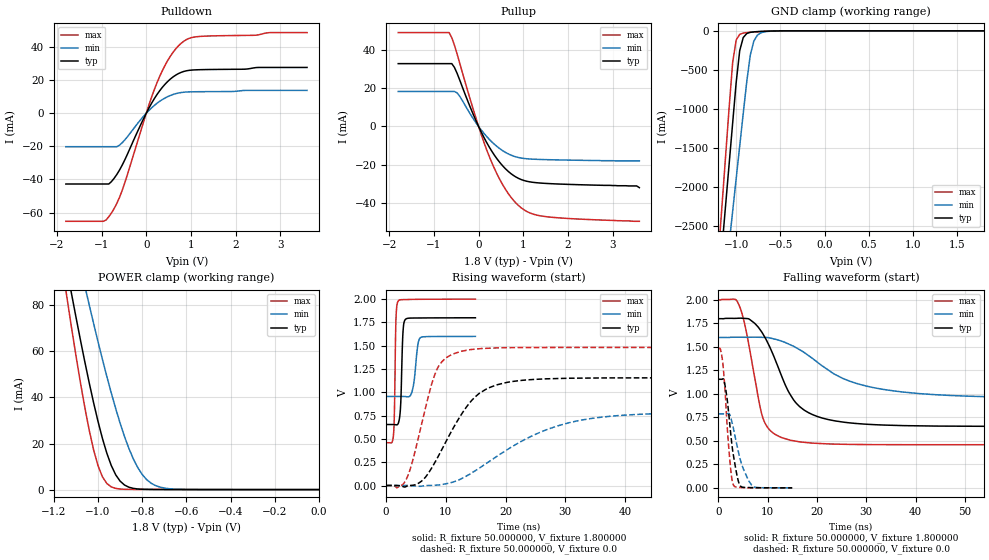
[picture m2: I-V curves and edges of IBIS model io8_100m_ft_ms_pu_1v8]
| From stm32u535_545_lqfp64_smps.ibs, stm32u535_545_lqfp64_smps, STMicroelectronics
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|   Model io8_100m_ft_ms_pu_1v8
[Model]  io8_100m_ft_ms_pu_1v8
Model_type I/O
Polarity   Non-Inverting
Enable   Active-Low
Vinl =   0.540000V
Vinh =   1.260000V
Vmeas =  0.900000V
Cref =   50.000000pF
Rref =   100.000000M
Vref =   0.0V
C_comp   3.148300pF   3.147400pF   3.196500pF
[Temperature Range]   25.000000   0.140000k   -40.000000
[Pullup Reference]   1.800000V   1.600000V   2.000000V
[Pulldown Reference]   0.0V   0.0V   0.0V
[POWER Clamp Reference]   1.800000V   1.600000V   2.000000V
[GND Clamp Reference]   0.0V   0.0V   0.0V
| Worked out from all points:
|   slope of the pulldown table from 0 to 0.27 V, typ, clamps not added: 21.7 ohm
|   slope of the pullup table from 0 to 0.27 V, typ, clamps not added: 22.6 ohm
|   GND clamp passes 1 mA (typ) near -0.51 V on its own axis
|   POWER clamp passes 1 mA (typ) near -0.86 V on its own axis
|   rising waveform, R_fixture 50.000000, V_fixture 1.800000: 20-80 % time 318ps typ, 631ps min, 230ps max; typ from 0.655 V to 1.8 V
|   rising waveform, R_fixture 50.000000, V_fixture 0.0: 20-80 % time 6.48ns typ, 13.4ns min, 3.57ns max; typ from 0.001 V to 1.16 V
|   falling waveform, R_fixture 50.000000, V_fixture 1.800000: 20-80 % time 6.36ns typ, 13.5ns min, 3.36ns max; typ from 1.8 V to 0.655 V
|   falling waveform, R_fixture 50.000000, V_fixture 0.0: 20-80 % time 1.6ns typ, 2.38ns min, 1.18ns max; typ from 1.16 V to 0.001 V
[Pulldown]
|Voltage   I(typ)   I(min)   I(max)
-1.8V     -42.74mA   -20.21mA   -65.25mA
-960mV    -42.74mA   -20.21mA   -65.25mA
-780mV    -41.3mA    -20.21mA   -60.25mA
-660mV    -37mA      -20.2mA    -54.5mA
-540mV    -31.39mA   -17.82mA   -46.65mA
0V        0A         0A         0A
240mV     11.28mA    6.002mA    18.38mA
480mV     19.17mA    10.02mA    31.83mA
780mV     24.67mA    12.5mA     42.21mA
960mV     25.9mA     12.9mA     45.21mA
1.2V      26.29mA    13.01mA    46.37mA
3.6V      27.65mA    13.81mA    48.71mA
[Pullup]
|Voltage   I(typ)   I(min)   I(max)
-1.8V     32.87mA    18.3mA     49.12mA
-660mV    32.87mA    18.3mA     49.12mA
-600mV    32.87mA    18.3mA     46.4mA
-480mV    27.73mA    17.56mA    37.8mA
-60mV     3.108mA    1.975mA    4.436mA
240mV     -10.82mA   -6.752mA   -15.73mA
420mV     -17.18mA   -10.64mA   -25.23mA
600mV     -22.1mA    -13.54mA   -32.82mA
960mV     -27.82mA   -16.55mA   -42.66mA
1.2V      -29.16mA   -17.09mA   -45.68mA
1.56V     -29.85mA   -17.37mA   -47.3mA
3.6V      -32mA      -18mA      -49.6mA
[GND_clamp]
|Voltage   I(typ)   I(min)   I(max)
-1.8V     -9.707A    -9.942A    -9.774A
-1.2V     -3.309A    -4.006A    -2.864A
-1.16V    -2.777A    -3.584A    -2.239A
-1.12V    -2.246A    -3.162A    -1.614A
-1.04V    -1.186A    -2.319A    -408.6mA
-1V       -663.9mA   -1.898A    -117.8mA
-960mV    -254mA     -1.478A    -45.14mA
-920mV    -86.03mA   -1.06A     -28.58mA
-840mV    -19.12mA   -308.9mA   -18.74mA
-800mV    -13.39mA   -130.8mA   -15.31mA
-720mV    -7.948mA   -25.37mA   -9.381mA
1.8V      0A         14.97nA    0A
[POWER_clamp]
|Voltage   I(typ)   I(min)   I(max)
-1.8V     470.9mA    433.7mA    554.6mA
-1.14V    95.28mA    122.7mA    82.88mA
-1.12V    85mA       114mA      70.34mA
-1.06V    55.55mA    88.43mA    35.73mA
-1.04V    46.38mA    80.17mA    25.83mA
-1V       29.54mA    64.14mA    10.37mA
-940mV    10.43mA    41.88mA    1.177mA
-900mV    3.66mA     28.79mA    250.5uA
-840mV    527.2uA    13.26mA    95.74uA
-800mV    153.8uA    6.55mA     88.56uA
-740mV    60.02uA    1.742mA    70.74uA
0V        0A         18.15nA    0A
[Ramp]
| variable   typ   min   max
dV/dt_r  0.69293/6.46989n   0.47197/13.34513n   0.88855/3.56212n
dV/dt_f  0.68715/6.35794n   0.38626/13.46817n   0.92439/3.34580n
R_load = 50.000000
[Rising Waveform]
R_fixture= 50.000000
V_fixture= 1.800000
V_fixture_min= 1.600000
V_fixture_max= 2.000000
|time   V(typ)   V(min)   V(max)
0s        654.8mV    956mV      459.4mV
1.231ns   654.6mV    956mV      545mV
1.652ns   651.9mV    956mV      1.797V
2.012ns   664.8mV    956.1mV    1.98V
2.432ns   868mV      956.1mV    1.993V
2.853ns   1.677V     955.8mV    1.995V
3.213ns   1.782V     954.8mV    1.995V
4.414ns   1.797V     1.027V     1.997V
5.676ns   1.798V     1.583V     1.998V
14.95ns   1.8V       1.6V       2V
[Rising Waveform]
R_fixture= 50.000000
V_fixture= 0.0
V_fixture_min= 0.0
V_fixture_max= 0.0
|time   V(typ)   V(min)   V(max)
0s        614.9uV    691.2uV    580.3uV
3.203ns   -15.29mV   805.6uV    47.33mV
6.006ns   51.57mV    -6.151mV   676.5mV
8.408ns   275.5mV    4.433mV    1.233V
12.61ns   763.6mV    73.78mV    1.441V
15.62ns   989.8mV    187.2mV    1.468V
18.42ns   1.078V     307.6mV    1.476V
26.83ns   1.145V     598mV      1.481V
35.44ns   1.154V     728.7mV    1.481V
99.7ns    1.155V     787.4mV    1.481V
[Falling Waveform]
R_fixture= 50.000000
V_fixture= 1.800000
V_fixture_min= 1.600000
V_fixture_max= 2.000000
|time   V(typ)   V(min)   V(max)
0s        1.8V       1.6V       2V
3.804ns   1.804V     1.603V     1.984V
5.405ns   1.802V     1.602V     1.721V
9.209ns   1.62V      1.601V     715.5mV
14.41ns   1.005V     1.526V     509.6mV
17.22ns   833.9mV    1.447V     485.7mV
21.02ns   743.6mV    1.299V     471.3mV
27.63ns   686.7mV    1.118V     462.3mV
37.04ns   663.3mV    1.022V     459.8mV
99.7ns    654.8mV    956mV      459.4mV
[Falling Waveform]
R_fixture= 50.000000
V_fixture= 0.0
V_fixture_min= 0.0
V_fixture_max= 0.0
|time   V(typ)   V(min)   V(max)
0s        1.155V     787.4mV    1.481V
750.8ps   1.156V     787.4mV    1.378V
1.321ns   1.092V     787.4mV    1.045V
1.802ns   924.2mV    788.9mV    624.3mV
2.282ns   680mV      779.7mV    305.1mV
2.673ns   482.7mV    712.5mV    111.3mV
3.033ns   344.4mV    630.9mV    30.74mV
4.234ns   40.12mV    341.2mV    5.571mV
6.727ns   3.287mV    29.26mV    1.626mV
14.95ns   614.9uV    691.2uV    580.3uV
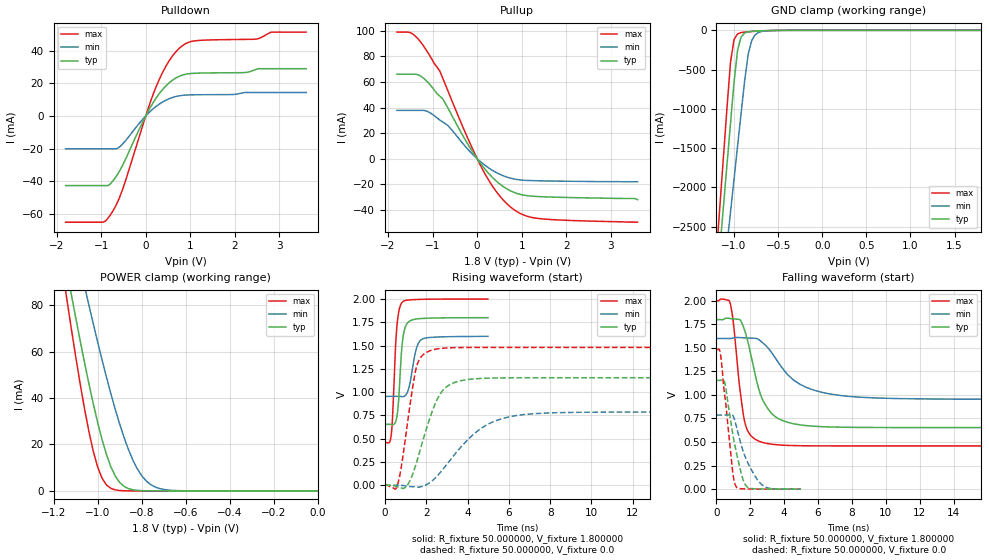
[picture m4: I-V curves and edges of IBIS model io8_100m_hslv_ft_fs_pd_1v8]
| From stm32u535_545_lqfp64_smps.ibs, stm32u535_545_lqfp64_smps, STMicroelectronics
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|   Model io8_100m_hslv_ft_fs_pd_1v8
[Model]  io8_100m_hslv_ft_fs_pd_1v8
Model_type I/O
Polarity   Non-Inverting
Enable   Active-Low
Vinl =   0.540000V
Vinh =   1.260000V
Vmeas =  0.900000V
Cref =   50.000000pF
Rref =   100.000000M
Vref =   0.0V
C_comp   3.235100pF   3.233200pF   3.282800pF
[Temperature Range]   25.000000   0.140000k   -40.000000
[Pullup Reference]   1.800000V   1.600000V   2.000000V
[Pulldown Reference]   0.0V   0.0V   0.0V
[POWER Clamp Reference]   1.800000V   1.600000V   2.000000V
[GND Clamp Reference]   0.0V   0.0V   0.0V
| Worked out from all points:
|   slope of the pulldown table from 0 to 0.27 V, typ, clamps not added: 21.7 ohm
|   slope of the pullup table from 0 to 0.27 V, typ, clamps not added: 22.6 ohm
|   GND clamp passes 1 mA (typ) near -0.51 V on its own axis
|   POWER clamp passes 1 mA (typ) near -0.86 V on its own axis
|   rising waveform, R_fixture 50.000000, V_fixture 1.800000: 20-80 % time 212ps typ, 327ps min, 198ps max; typ from 0.654 V to 1.8 V
|   rising waveform, R_fixture 50.000000, V_fixture 0.0: 20-80 % time 1.02ns typ, 2.03ns min, 582ps max; typ from 0 V to 1.15 V
|   falling waveform, R_fixture 50.000000, V_fixture 1.800000: 20-80 % time 1.09ns typ, 2.1ns min, 568ps max; typ from 1.8 V to 0.654 V
|   falling waveform, R_fixture 50.000000, V_fixture 0.0: 20-80 % time 708ps typ, 987ps min, 509ps max; typ from 1.15 V to 0 V
[Pulldown]
|Voltage   I(typ)   I(min)   I(max)
-1.8V     -42.74mA   -20.21mA   -65.25mA
-960mV    -42.74mA   -20.21mA   -65.25mA
-780mV    -41.3mA    -20.21mA   -60.25mA
-540mV    -31.39mA   -17.82mA   -46.65mA
0V        0A         -500fA     0A
240mV     11.28mA    6.002mA    18.38mA
480mV     19.17mA    10.02mA    31.83mA
780mV     24.67mA    12.5mA     42.21mA
1.14V     26.24mA    12.99mA    46.23mA
2.46V     28.42mA    14.39mA    47.14mA
2.82V     29mA       14.39mA    51.49mA
3.6V      29mA       14.39mA    51.49mA
[Pullup]
|Voltage   I(typ)   I(min)   I(max)
-1.8V     66.02mA    37.77mA    98.95mA
-1.44V    66.02mA    37.77mA    97.33mA
-1.14V    60.88mA    37.29mA    84.79mA
-840mV    48.93mA    30.23mA    68.56mA
-660mV    39.81mA    25.95mA    53.26mA
-300mV    16.72mA    11mA       23.08mA
120mV     -5.748mA   -3.603mA   -8.317mA
420mV     -17.18mA   -10.64mA   -25.23mA
780mV     -25.61mA   -15.48mA   -38.6mA
1.08V     -28.66mA   -16.9mA    -44.47mA
1.38V     -29.58mA   -17.26mA   -46.72mA
3.6V      -32mA      -18mA      -49.6mA
[GND_clamp]
|Voltage   I(typ)   I(min)   I(max)
-1.8V     -9.707A    -9.942A    -9.774A
-1.2V     -3.309A    -4.006A    -2.865A
-1.16V    -2.777A    -3.584A    -2.239A
-1.12V    -2.246A    -3.162A    -1.614A
-1.04V    -1.186A    -2.319A    -408.7mA
-1V       -663.9mA   -1.898A    -117.8mA
-960mV    -254mA     -1.478A    -45.15mA
-920mV    -86.04mA   -1.06A     -28.6mA
-840mV    -19.13mA   -308.9mA   -18.75mA
-800mV    -13.4mA    -130.8mA   -15.33mA
-720mV    -7.959mA   -25.38mA   -9.395mA
1.8V      45.71uA    33.33uA    56.11uA
[POWER_clamp]
|Voltage   I(typ)   I(min)   I(max)
-1.8V     470.8mA    433.7mA    554.6mA
-1.14V    95.25mA    122.7mA    82.82mA
-1.12V    84.97mA    114mA      70.27mA
-1.06V    55.51mA    88.42mA    35.67mA
-1.04V    46.34mA    80.15mA    25.76mA
-1V       29.51mA    64.13mA    10.3mA
-940mV    10.39mA    41.86mA    1.109mA
-900mV    3.624mA    28.77mA    182.8uA
-840mV    490.7uA    13.24mA    11.35uA
-800mV    116.8uA    6.532mA    1.77uA
-740mV    13.2uA     1.723mA    109.2nA
0V        0A         18.72nA    0A
[Ramp]
| variable   typ   min   max
dV/dt_r  0.69258/1.02276n   0.47168/2.03115n   0.88830/0.58108n
dV/dt_f  0.68752/1.08521n   0.38689/2.09532n   0.92452/0.56669n
R_load = 50.000000
[Rising Waveform]
R_fixture= 50.000000
V_fixture= 1.800000
V_fixture_min= 1.600000
V_fixture_max= 2.000000
|time   V(typ)   V(min)   V(max)
0s        653.7mV    954.5mV    458.6mV
310.3ps   652.7mV    954.7mV    549.8mV
370.4ps   650.7mV    954.8mV    746.8mV
550.6ps   707.2mV    955mV      1.628V
650.7ps   879mV      955mV      1.839V
810.8ps   1.456V     952.3mV    1.957V
1.061ns   1.733V     986.6mV    1.987V
1.512ns   1.785V     1.46V      1.994V
1.782ns   1.791V     1.566V     1.996V
4.985ns   1.799V     1.599V     1.999V
[Rising Waveform]
R_fixture= 50.000000
V_fixture= 0.0
V_fixture_min= 0.0
V_fixture_max= 0.0
|time   V(typ)   V(min)   V(max)
0s        -120.5uV   -24.73uV   -133uV
600.6ps   -17.03mV   -53.11uV   -896uV
1.041ns   -10.8mV    -9.086mV   586mV
1.522ns   239.4mV    -19.39mV   1.267V
2.242ns   764.7mV    40.38mV    1.449V
2.763ns   1.008V     159.9mV    1.47V
3.363ns   1.103V     327.7mV    1.478V
4.805ns   1.148V     631.7mV    1.48V
6.206ns   1.153V     742.7mV    1.48V
19.94ns   1.155V     786.3mV    1.48V
[Falling Waveform]
R_fixture= 50.000000
V_fixture= 1.800000
V_fixture_min= 1.600000
V_fixture_max= 2.000000
|time   V(typ)   V(min)   V(max)
0s        1.799V     1.599V     1.999V
800.8ps   1.811V     1.599V     1.983V
1.001ns   1.807V     1.606V     1.768V
1.361ns   1.8V       1.609V     1.103V
1.642ns   1.699V     1.606V     741.3mV
2.482ns   1.075V     1.589V     511.5mV
3.564ns   759.1mV    1.369V     471.5mV
4.525ns   695.2mV    1.162V     462.8mV
6.326ns   662.6mV    1.024V     459mV
19.94ns   653.7mV    954.5mV    458.6mV
[Falling Waveform]
R_fixture= 50.000000
V_fixture= 0.0
V_fixture_min= 0.0
V_fixture_max= 0.0
|time   V(typ)   V(min)   V(max)
0s        1.155V     786.3mV    1.48V
240.2ps   1.155V     786.3mV    1.433V
480.5ps   1.139V     786.4mV    1.011V
971ps     582.1mV    780.6mV    173.5mV
1.171ns   396.8mV    672.3mV    25.18mV
1.502ns   144.4mV    447.4mV    4.102mV
1.712ns   46.4mV     338.6mV    2.742mV
2.573ns   2.51mV     65.95mV    737.1uV
3.273ns   945uV      5.496mV    216.1uV
4.985ns   -120.5uV   -24.73uV   -133uV
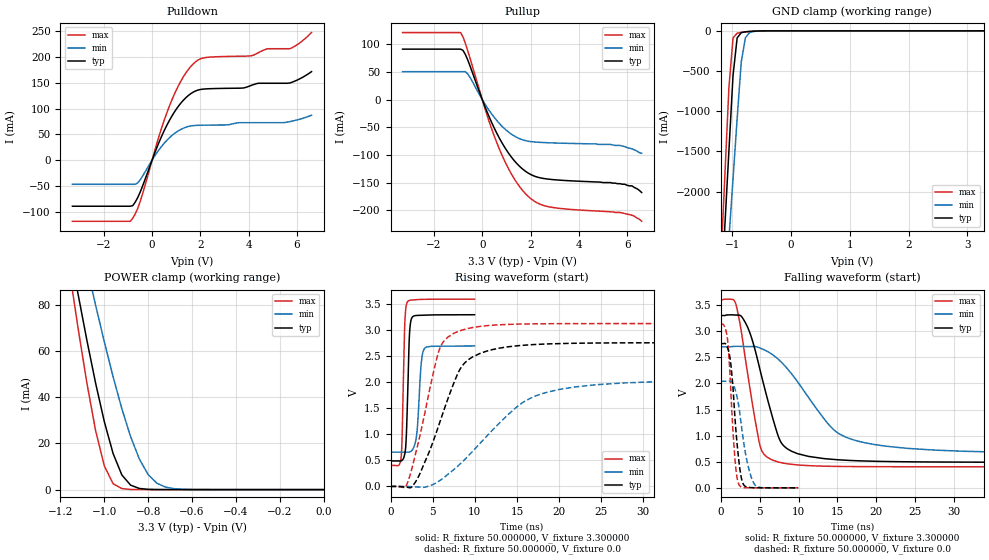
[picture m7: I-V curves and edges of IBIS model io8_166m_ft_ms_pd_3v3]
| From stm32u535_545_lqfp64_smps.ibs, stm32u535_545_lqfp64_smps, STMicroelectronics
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|   Model io8_166m_ft_ms_pd_3v3
[Model]  io8_166m_ft_ms_pd_3v3
Model_type I/O
Polarity   Non-Inverting
Enable   Active-Low
Vinl =   0.990000V
Vinh =   2.310000V
Vmeas =  1.650000V
Cref =   50.000000pF
Rref =   100.000000M
Vref =   0.0V
C_comp   3.517200pF   3.489400pF   3.557800pF
[Temperature Range]   25.000000   0.140000k   -40.000000
[Pullup Reference]   3.300000V   2.700000V   3.600000V
[Pulldown Reference]   0.0V   0.0V   0.0V
[POWER Clamp Reference]   3.300000V   2.700000V   3.600000V
[GND Clamp Reference]   0.0V   0.0V   0.0V
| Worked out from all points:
|   slope of the pulldown table from 0 to 0.495 V, typ, clamps not added: 8.73 ohm
|   slope of the pullup table from 0 to 0.495 V, typ, clamps not added: 9.64 ohm
|   GND clamp passes 1 mA (typ) near -0.50 V on its own axis
|   POWER clamp passes 1 mA (typ) near -0.85 V on its own axis
|   rising waveform, R_fixture 50.000000, V_fixture 3.300000: 20-80 % time 306ps typ, 454ps min, 272ps max; typ from 0.49 V to 3.3 V
|   rising waveform, R_fixture 50.000000, V_fixture 0.0: 20-80 % time 3.81ns typ, 7.8ns min, 2.6ns max; typ from 0 V to 2.76 V
|   falling waveform, R_fixture 50.000000, V_fixture 3.300000: 20-80 % time 3.02ns typ, 6.39ns min, 2.05ns max; typ from 3.3 V to 0.49 V
|   falling waveform, R_fixture 50.000000, V_fixture 0.0: 20-80 % time 900ps typ, 1.3ns min, 735ps max; typ from 2.76 V to 0 V
[Pulldown]
|Voltage   I(typ)   I(min)   I(max)
-3.3V     -89.72mA   -47.06mA   -119mA
-900mV    -89.72mA   -47.06mA   -119mA
-500mV    -62.92mA   -38.71mA   -81.44mA
300mV     36.2mA     21.01mA    48.7mA
800mV     84.07mA    46.96mA    114.9mA
1.3V      116.7mA    62.09mA    162.4mA
1.8V      134.4mA    67.39mA    191.2mA
2.3V      138.6mA    67.98mA    199.8mA
4.1V      145.1mA    72.79mA    202.7mA
4.8V      149.4mA    72.79mA    216.5mA
5.7V      149.8mA    74.8mA     216.5mA
6.6V      171.9mA    87.1mA     247.9mA
[Pullup]
|Voltage   I(typ)   I(min)   I(max)
-3.3V     91.09mA    50.39mA    121mA
-900mV    91.09mA    50.39mA    121mA
-800mV    88.97mA    50.39mA    113.5mA
-600mV    71.54mA    46.26mA    88.13mA
200mV     -22.26mA   -14.13mA   -28.39mA
700mV     -69mA      -42.82mA   -88.5mA
1.3V      -109.1mA   -65.19mA   -141.4mA
2V        -135.3mA   -75.91mA   -178.7mA
2.9V      -144.6mA   -78.33mA   -194.9mA
5.3V      -150mA     -81mA      -203mA
6.2V      -156mA     -89mA      -209mA
6.6V      -168mA     -97mA      -220mA
[GND_clamp]
|Voltage   I(typ)   I(min)   I(max)
-3.3V     -9.098A    -9.372A    -9.671A
-1.2V     -3.386A    -4.091A    -2.933A
-1.13V    -2.437A    -3.34A     -1.815A
-1.06V    -1.49A     -2.588A    -705.6mA
-990mV    -555.7mA   -1.839A    -89.05mA
-920mV    -88.14mA   -1.093A    -28.79mA
-850mV    -22.37mA   -387.4mA   -19.86mA
-780mV    -12.13mA   -88.01mA   -13.89mA
-710mV    -7.72mA    -22.53mA   -8.86mA
-640mV    -4.556mA   -7.872mA   -4.884mA
-360mV    -39.7uA    -179.9uA   -19.45uA
3.28V     83.52uA    56.87uA    102.4uA
[POWER_clamp]
|Voltage   I(typ)   I(min)   I(max)
-3.28V    1.355A     1.167A     1.664A
-1.16V    105.7mA    131.6mA    95.69mA
-1.12V    84.97mA    114mA      70.27mA
-1.08V    65.05mA    96.83mA    46.54mA
-1.04V    46.34mA    80.15mA    25.76mA
-1V       29.51mA    64.13mA    10.3mA
-960mV    15.69mA    48.99mA    2.571mA
-920mV    6.373mA    35.1mA     455.6uA
-840mV    490.7uA    13.24mA    11.36uA
-760mV    27.33uA    2.767mA    278.3nA
-640mV    347.6nA    134.1uA    16.77nA
0V        0A         19.95nA    0A
[Ramp]
| variable   typ   min   max
dV/dt_r  1.65672/3.80420n   1.22400/7.77794n   1.87818/2.59374n
dV/dt_f  1.68576/3.01399n   1.22231/6.38035n   1.91752/2.04801n
R_load = 50.000000
[Rising Waveform]
R_fixture= 50.000000
V_fixture= 3.300000
V_fixture_min= 2.700000
V_fixture_max= 3.600000
|time   V(typ)   V(min)   V(max)
0s        489.8mV    659.5mV    403.4mV
1.261ns   490.8mV    659.5mV    572.3mV
1.682ns   622.2mV    659.3mV    3.097V
1.982ns   1.514V     658.1mV    3.54V
2.242ns   2.913V     661.7mV    3.575V
2.583ns   3.253V     702.2mV    3.582V
3.103ns   3.285V     999.3mV    3.589V
3.604ns   3.288V     2.297V     3.594V
3.964ns   3.29V      2.635V     3.596V
9.97ns    3.299V     2.699V     3.599V
[Rising Waveform]
R_fixture= 50.000000
V_fixture= 0.0
V_fixture_min= 0.0
V_fixture_max= 0.0
|time   V(typ)   V(min)   V(max)
0s        5.267uV    5.722uV    3.565uV
1.802ns   -13.17mV   184.5uV    -5.443mV
3.003ns   97.32mV    -9.833mV   653.5mV
5.766ns   1.195V     103.3mV    2.618V
8.168ns   2.23V      417.3mV    2.988V
10.69ns   2.561V     839.7mV    3.077V
15.26ns   2.706V     1.562V     3.119V
20.06ns   2.744V     1.865V     3.128V
31.11ns   2.76V      2.009V     3.13V
59.82ns   2.761V     2.04V      3.13V
[Falling Waveform]
R_fixture= 50.000000
V_fixture= 3.300000
V_fixture_min= 2.700000
V_fixture_max= 3.600000
|time   V(typ)   V(min)   V(max)
0s        3.299V     2.699V     3.599V
1.922ns   3.308V     2.709V     3.53V
3.483ns   3.067V     2.705V     2.165V
5.045ns   2.263V     2.677V     811.7mV
6.727ns   1.313V     2.543V     527.4mV
7.688ns   887.6mV    2.421V     484.8mV
9.129ns   699.5mV    2.179V     451mV
14.29ns   547.3mV    1.144V     412.2mV
17.9ns    517mV      884.8mV    406.7mV
59.82ns   489.8mV    659.5mV    403.4mV
[Falling Waveform]
R_fixture= 50.000000
V_fixture= 0.0
V_fixture_min= 0.0
V_fixture_max= 0.0
|time   V(typ)   V(min)   V(max)
0s        2.761V     2.04V      3.13V
800.8ps   2.713V     2.04V      2.922V
1.201ns   2.482V     2.045V     2.165V
1.562ns   1.954V     1.993V     1.127V
1.822ns   1.365V     1.899V     574.6mV
2.342ns   505.9mV    1.545V     64.75mV
2.943ns   61.64mV    878.9mV    5.232mV
3.564ns   9.187mV    394.1mV    1.867mV
4.344ns   2.718mV    67.38mV    966.5uV
9.97ns    5.267uV    5.722uV    3.565uV
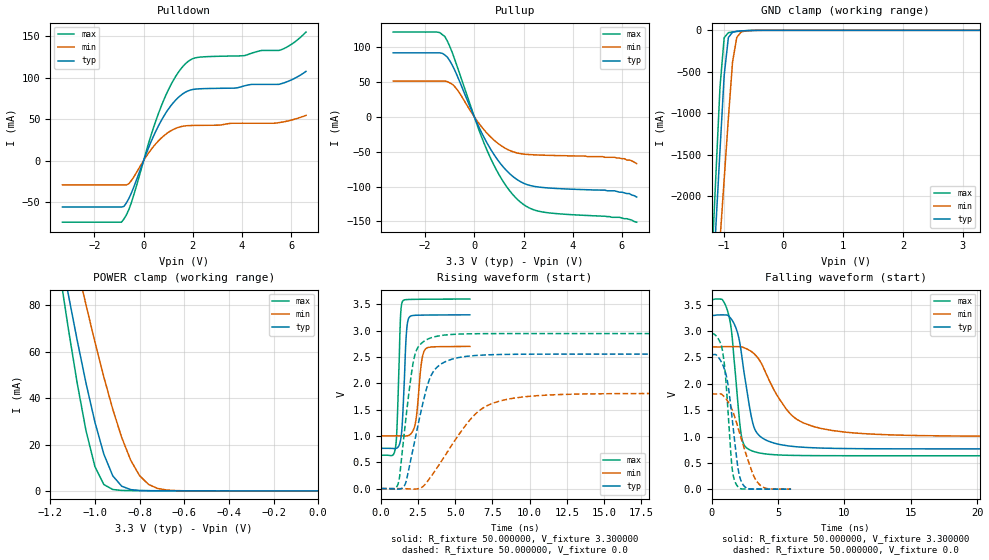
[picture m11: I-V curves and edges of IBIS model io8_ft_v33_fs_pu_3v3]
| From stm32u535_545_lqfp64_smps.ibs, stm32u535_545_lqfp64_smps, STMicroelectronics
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|   Model io8_ft_v33_fs_pu_3v3
[Model]  io8_ft_v33_fs_pu_3v3
Model_type I/O
Polarity   Non-Inverting
Enable   Active-Low
Vinl =   0.990000V
Vinh =   2.310000V
Vmeas =  1.650000V
Cref =   50.000000pF
Rref =   100.000000M
Vref =   0.0V
C_comp   3.252200pF   3.221000pF   3.293600pF
[Temperature Range]   25.000000   0.140000k   -40.000000
[Pullup Reference]   3.300000V   2.700000V   3.600000V
[Pulldown Reference]   0.0V   0.0V   0.0V
[POWER Clamp Reference]   3.300000V   2.700000V   3.600000V
[GND Clamp Reference]   0.0V   0.0V   0.0V
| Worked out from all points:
|   slope of the pulldown table from 0 to 0.495 V, typ, clamps not added: 14 ohm
|   slope of the pullup table from 0 to 0.495 V, typ, clamps not added: 13.7 ohm
|   GND clamp passes 1 mA (typ) near -0.51 V on its own axis
|   POWER clamp passes 1 mA (typ) near -0.85 V on its own axis
|   rising waveform, R_fixture 50.000000, V_fixture 3.300000: 20-80 % time 236ps typ, 337ps min, 193ps max; typ from 0.765 V to 3.3 V
|   rising waveform, R_fixture 50.000000, V_fixture 0.0: 20-80 % time 1.24ns typ, 2.78ns min, 755ps max; typ from 0.001 V to 2.55 V
|   falling waveform, R_fixture 50.000000, V_fixture 3.300000: 20-80 % time 973ps typ, 2.53ns min, 635ps max; typ from 3.3 V to 0.765 V
|   falling waveform, R_fixture 50.000000, V_fixture 0.0: 20-80 % time 731ps typ, 1.36ns min, 509ps max; typ from 2.55 V to 0.001 V
[Pulldown]
|Voltage   I(typ)   I(min)   I(max)
-3.3V     -56.06mA   -29.42mA   -74.35mA
-900mV    -56.06mA   -29.42mA   -74.35mA
-700mV    -51.09mA   -29.42mA   -65.48mA
-500mV    -39.32mA   -24.2mA    -50.88mA
300mV     22.62mA    13.13mA    30.42mA
800mV     52.54mA    29.36mA    71.75mA
1.3V      72.91mA    38.82mA    101.4mA
1.8V      84.02mA    42.13mA    119.4mA
2.3V      86.61mA    42.5mA     124.8mA
5.5V      91.96mA    45.75mA    132.9mA
6.1V      98.6mA     49.6mA     142.1mA
6.6V      107.6mA    54.5mA     155mA
[Pullup]
|Voltage   I(typ)   I(min)   I(max)
-3.3V     91.68mA    51.24mA    121.4mA
-1.5V     91.68mA    51.24mA    121.4mA
-1.2V     88.66mA    51.24mA    115.2mA
-800mV    67.14mA    43.45mA    82.65mA
100mV     -8.009mA   -5.102mA   -10.2mA
600mV     -42.64mA   -26.6mA    -54.61mA
1.2V      -72.81mA   -43.84mA   -94.18mA
1.9V      -93.37mA   -52.9mA    -122.9mA
2.3V      -98.71mA   -54.23mA   -131.6mA
2.8V      -101.3mA   -54.97mA   -136.5mA
5.7V      -106mA     -58mA      -144mA
6.6V      -115mA     -67mA      -151mA
[GND_clamp]
|Voltage   I(typ)   I(min)   I(max)
-3.3V     -9.848A    -9.957A    -9.458A
-1.2V     -3.312A    -4.013A    -2.863A
-1.13V    -2.381A    -3.274A    -1.769A
-1.06V    -1.452A    -2.535A    -684.7mA
-990mV    -542.9mA   -1.798A    -88.02mA
-920mV    -87.11mA   -1.064A    -28.44mA
-850mV    -22.1mA    -382.4mA   -19.61mA
-780mV    -11.97mA   -86.98mA   -13.71mA
-710mV    -7.619mA   -22.26mA   -8.745mA
-640mV    -4.493mA   -7.773mA   -4.817mA
-360mV    -31.22uA   -172.6uA   -8.607uA
3.28V     0A         15.66nA    -5.841nA
[POWER_clamp]
|Voltage   I(typ)   I(min)   I(max)
-3.28V    1.355A     1.167A     1.665A
-1.16V    105.8mA    131.6mA    95.87mA
-1.12V    85.09mA    114mA      70.46mA
-1.08V    65.2mA     96.88mA    46.75mA
-1.04V    46.48mA    80.2mA     25.96mA
-1V       29.64mA    64.18mA    10.49mA
-960mV    15.81mA    49.06mA    2.744mA
-920mV    6.482mA    35.16mA    613.3uA
-840mV    578.4uA    13.29mA    138.7uA
-760mV    94.46uA    2.808mA    98.68uA
-640mV    40.58uA    159.2uA    60uA
0V        0A         19.29nA    0A
[Ramp]
| variable   typ   min   max
dV/dt_r  1.53214/1.24163n   1.08405/2.77161n   1.76624/0.75385n
dV/dt_f  1.52095/0.97144n   1.01820/2.52766n   1.77908/0.63307n
R_load = 50.000000
[Rising Waveform]
R_fixture= 50.000000
V_fixture= 3.300000
V_fixture_min= 2.700000
V_fixture_max= 3.600000
|time   V(typ)   V(min)   V(max)
0s        765.1mV    1.003V     634.9mV
985ps     761.9mV    1.003V     793.2mV
1.093ns   774.2mV    1.003V     1.262V
1.309ns   906.5mV    1.002V     3.219V
1.453ns   1.332V     1.001V     3.558V
1.706ns   2.926V     1V         3.589V
1.898ns   3.252V     1.015V     3.592V
2.342ns   3.292V     1.285V     3.595V
2.931ns   3.295V     2.627V     3.596V
5.982ns   3.3V       2.7V       3.6V
[Rising Waveform]
R_fixture= 50.000000
V_fixture= 0.0
V_fixture_min= 0.0
V_fixture_max= 0.0
|time   V(typ)   V(min)   V(max)
0s        858.8uV    874.2uV    898.1uV
1.141ns   -9.384mV   928.8uV    79.26mV
1.622ns   79.78mV    -514.7uV   1.189V
2.282ns   919.7mV    -8.782mV   2.539V
3.003ns   1.832V     93.94mV    2.818V
3.423ns   2.175V     252.6mV    2.869V
4.444ns   2.425V     686.6mV    2.92V
6.186ns   2.524V     1.37V      2.941V
8.348ns   2.549V     1.688V     2.944V
29.91ns   2.554V     1.808V     2.944V
[Falling Waveform]
R_fixture= 50.000000
V_fixture= 3.300000
V_fixture_min= 2.700000
V_fixture_max= 3.600000
|time   V(typ)   V(min)   V(max)
0s        3.3V       2.7V       3.6V
1.201ns   3.302V     2.706V     3.385V
1.502ns   3.222V     2.706V     2.997V
1.802ns   3.079V     2.706V     2.159V
2.282ns   2.51V      2.7V       962.1mV
3.063ns   1.294V     2.601V     725mV
3.844ns   967.9mV    2.34V      677.7mV
6.006ns   815.5mV    1.409V     642.6mV
8.288ns   780.7mV    1.151V     636.6mV
29.91ns   765.1mV    1.003V     634.9mV
[Falling Waveform]
R_fixture= 50.000000
V_fixture= 0.0
V_fixture_min= 0.0
V_fixture_max= 0.0
|time   V(typ)   V(min)   V(max)
0s        2.554V     1.808V     2.944V
528.5ps   2.498V     1.81V      2.844V
840.8ps   2.357V     1.784V     2.591V
1.069ns   2.192V     1.721V     2.076V
1.526ns   1.393V     1.52V      445.4mV
1.838ns   691.6mV    1.295V     101mV
2.054ns   304.1mV    1.112V     30.07mV
2.366ns   86.42mV    849.1mV    3.638mV
3.483ns   2.405mV    121.2mV    1.755mV
5.982ns   858.8uV    874.2uV    898.1uV
